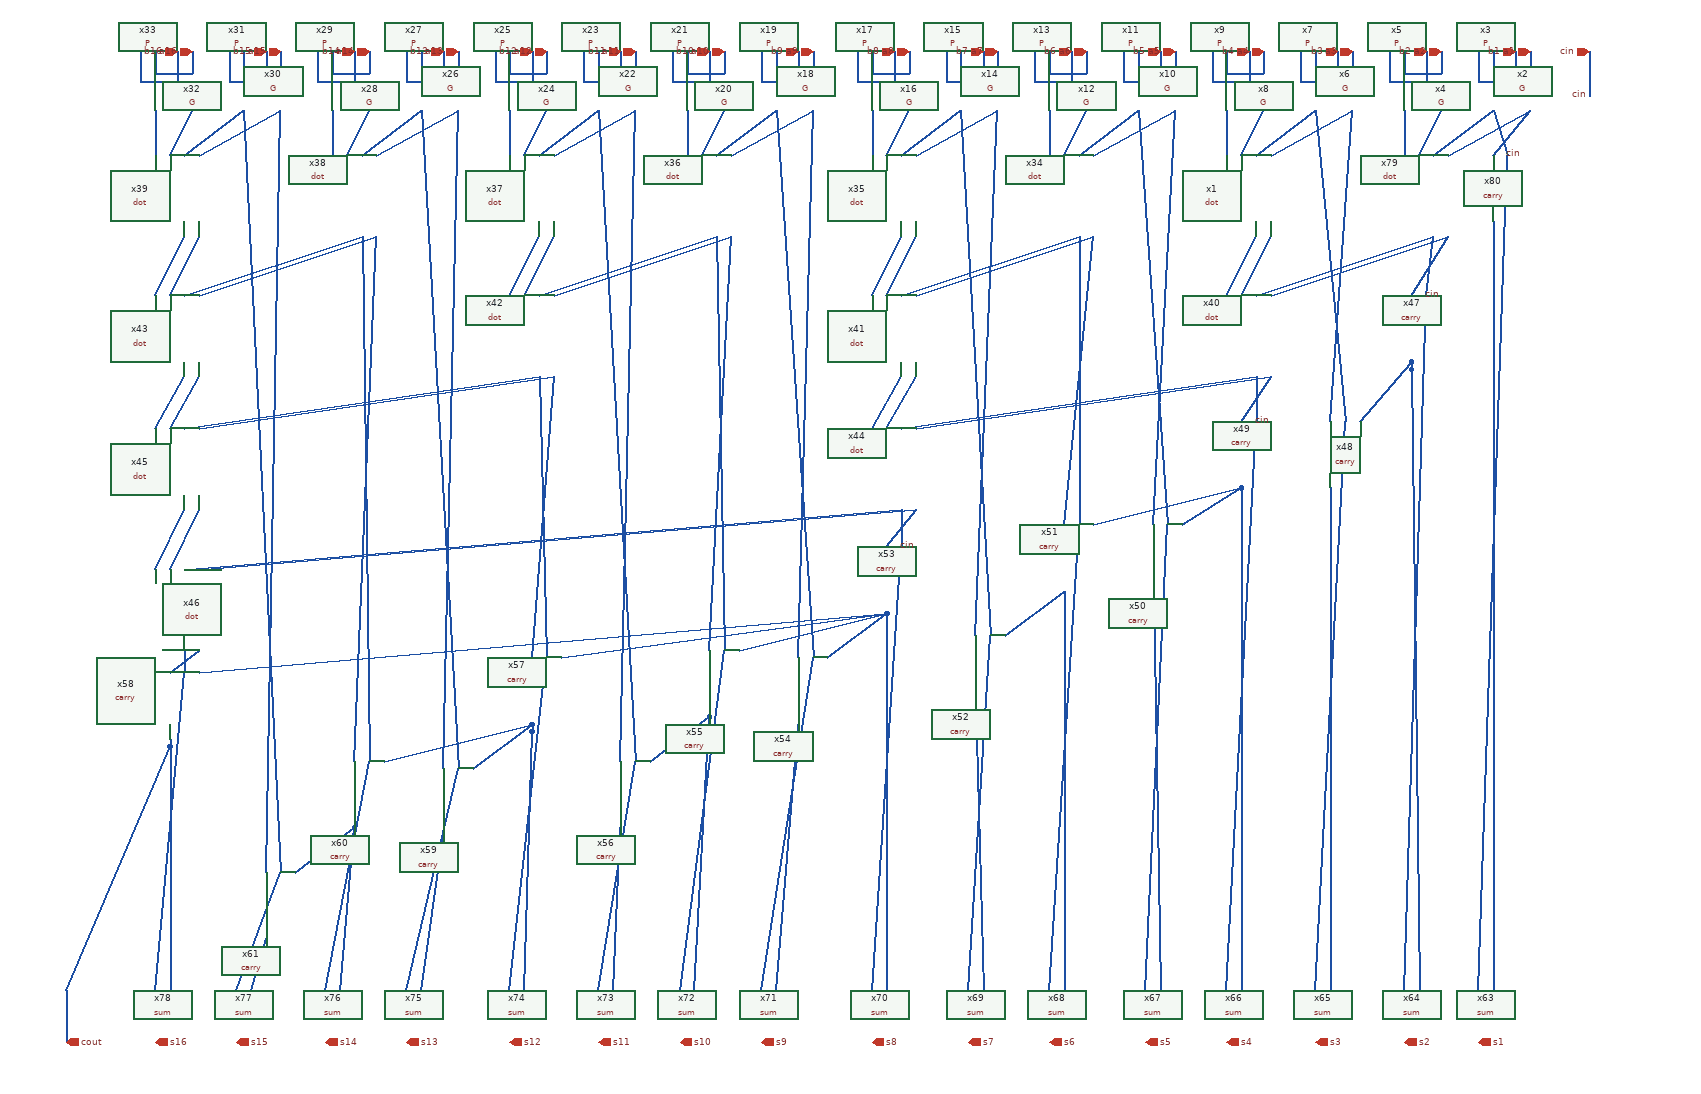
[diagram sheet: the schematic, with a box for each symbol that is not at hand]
v {xschem version=3.4.6 file_version=1.2}
G {}
K {}
V {}
S {}
E {}
N 1020 -110 1020 -50 {lab=cin}
N 940 -110 940 -80 {lab=a1}
N 890 -80 940 -80 {lab=a1}
N 890 -110 890 -80 {lab=a1}
N 920 -110 920 -70 {lab=b1}
N 870 -70 920 -70 {lab=b1}
N 870 -110 870 -70 {lab=b1}
N 820 -110 820 -80 {lab=a2}
N 770 -80 820 -80 {lab=a2}
N 770 -110 770 -80 {lab=a2}
N 800 -110 800 -70 {lab=b2}
N 750 -70 800 -70 {lab=b2}
N 750 -110 750 -70 {lab=b2}
N 700 -110 700 -80 {lab=a3}
N 650 -80 700 -80 {lab=a3}
N 650 -110 650 -80 {lab=a3}
N 680 -110 680 -70 {lab=b3}
N 630 -70 680 -70 {lab=b3}
N 630 -110 630 -70 {lab=b3}
N 580 -110 580 -80 {lab=a4}
N 530 -80 580 -80 {lab=a4}
N 530 -110 530 -80 {lab=a4}
N 560 -110 560 -70 {lab=b4}
N 510 -70 560 -70 {lab=b4}
N 510 -110 510 -70 {lab=b4}
N 460 -110 460 -80 {lab=a5}
N 410 -80 460 -80 {lab=a5}
N 410 -110 410 -80 {lab=a5}
N 440 -110 440 -70 {lab=b5}
N 390 -70 440 -70 {lab=b5}
N 390 -110 390 -70 {lab=b5}
N 340 -110 340 -80 {lab=a6}
N 290 -80 340 -80 {lab=a6}
N 290 -110 290 -80 {lab=a6}
N 320 -110 320 -70 {lab=b6}
N 270 -70 320 -70 {lab=b6}
N 270 -110 270 -70 {lab=b6}
N 220 -110 220 -80 {lab=a7}
N 170 -80 220 -80 {lab=a7}
N 170 -110 170 -80 {lab=a7}
N 200 -110 200 -70 {lab=b7}
N 150 -70 200 -70 {lab=b7}
N 150 -110 150 -70 {lab=b7}
N 100 -110 100 -80 {lab=a8}
N 50 -80 100 -80 {lab=a8}
N 50 -110 50 -80 {lab=a8}
N 80 -110 80 -70 {lab=b8}
N 30 -70 80 -70 {lab=b8}
N 30 -110 30 -70 {lab=b8}
N -30 -110 -30 -80 {lab=a9}
N -80 -80 -30 -80 {lab=a9}
N -80 -110 -80 -80 {lab=a9}
N -50 -110 -50 -70 {lab=b9}
N -100 -70 -50 -70 {lab=b9}
N -100 -110 -100 -70 {lab=b9}
N -150 -110 -150 -80 {lab=a10}
N -200 -80 -150 -80 {lab=a10}
N -200 -110 -200 -80 {lab=a10}
N -170 -110 -170 -70 {lab=b10}
N -220 -70 -170 -70 {lab=b10}
N -220 -110 -220 -70 {lab=b10}
N -270 -110 -270 -80 {lab=a11}
N -320 -80 -270 -80 {lab=a11}
N -320 -110 -320 -80 {lab=a11}
N -290 -110 -290 -70 {lab=b11}
N -340 -70 -290 -70 {lab=b11}
N -340 -110 -340 -70 {lab=b11}
N -390 -110 -390 -80 {lab=a12}
N -440 -80 -390 -80 {lab=a12}
N -440 -110 -440 -80 {lab=a12}
N -410 -110 -410 -70 {lab=b12}
N -460 -70 -410 -70 {lab=b12}
N -460 -110 -460 -70 {lab=b12}
N -510 -110 -510 -80 {lab=a13}
N -560 -80 -510 -80 {lab=a13}
N -560 -110 -560 -80 {lab=a13}
N -530 -110 -530 -70 {lab=b13}
N -580 -70 -530 -70 {lab=b13}
N -580 -110 -580 -70 {lab=b13}
N -630 -110 -630 -80 {lab=a14}
N -680 -80 -630 -80 {lab=a14}
N -680 -110 -680 -80 {lab=a14}
N -650 -110 -650 -70 {lab=b14}
N -700 -70 -650 -70 {lab=b14}
N -700 -110 -700 -70 {lab=b14}
N -750 -110 -750 -80 {lab=a15}
N -800 -80 -750 -80 {lab=a15}
N -800 -110 -800 -80 {lab=a15}
N -770 -110 -770 -70 {lab=b15}
N -820 -70 -770 -70 {lab=b15}
N -820 -110 -820 -70 {lab=b15}
N -870 -110 -870 -80 {lab=a16}
N -920 -80 -870 -80 {lab=a16}
N -920 -110 -920 -80 {lab=a16}
N -890 -110 -890 -70 {lab=b16}
N -940 -70 -890 -70 {lab=b16}
N -940 -110 -940 -70 {lab=b16}
N -1040 1160 -1040 1230 {lab=cout}
N 770 -30 770 30 {lab=#net1}
N 790 30 820 -30 {lab=#net2}
N 810 30 890 -30 {lab=#net3}
N 830 30 940 -30 {lab=#net4}
N 530 -30 530 30 {lab=#net5}
N 550 30 580 -30 {lab=#net6}
N 570 30 650 -30 {lab=#net7}
N 590 30 700 -30 {lab=#net8}
N 290 -30 290 30 {lab=#net9}
N 310 30 340 -30 {lab=#net10}
N 330 30 410 -30 {lab=#net11}
N 350 30 460 -30 {lab=#net12}
N 50 -30 50 30 {lab=#net13}
N 70 30 100 -30 {lab=#net14}
N 90 30 170 -30 {lab=#net15}
N 110 30 220 -30 {lab=#net16}
N -200 -30 -200 30 {lab=#net17}
N -180 30 -150 -30 {lab=#net18}
N -160 30 -80 -30 {lab=#net19}
N -140 30 -30 -30 {lab=#net20}
N -440 -30 -440 30 {lab=#net21}
N -420 30 -390 -30 {lab=#net22}
N -400 30 -320 -30 {lab=#net23}
N -380 30 -270 -30 {lab=#net24}
N -680 -30 -680 30 {lab=#net25}
N -660 30 -630 -30 {lab=#net26}
N -640 30 -560 -30 {lab=#net27}
N -620 30 -510 -30 {lab=#net28}
N -920 -30 -920 30 {lab=#net29}
N -900 30 -870 -30 {lab=#net30}
N -880 30 -800 -30 {lab=#net31}
N -860 30 -750 -30 {lab=#net32}
N 530 220 570 140 {lab=#net33}
N 550 220 590 140 {lab=#net34}
N 570 220 810 140 {lab=#net35}
N 590 220 830 140 {lab=#net36}
N 50 220 90 140 {lab=#net37}
N 70 220 110 140 {lab=#net38}
N 90 220 330 140 {lab=#net39}
N 110 220 350 140 {lab=#net40}
N -440 220 -400 140 {lab=#net41}
N -420 220 -380 140 {lab=#net42}
N -400 220 -160 140 {lab=#net43}
N -380 220 -140 140 {lab=#net44}
N -920 220 -880 140 {lab=#net45}
N -900 220 -860 140 {lab=#net46}
N -880 220 -640 140 {lab=#net47}
N -860 220 -620 140 {lab=#net48}
N 50 400 90 330 {lab=#net49}
N 70 400 110 330 {lab=#net50}
N 90 400 570 330 {lab=#net51}
N 110 400 590 330 {lab=#net52}
N -920 400 -880 330 {lab=#net53}
N -900 400 -860 330 {lab=#net54}
N -880 400 -400 330 {lab=#net55}
N -860 400 -380 330 {lab=#net56}
N -920 590 -880 510 {lab=#net57}
N -900 590 -860 510 {lab=#net58}
N -880 590 90 510 {lab=#net59}
N -860 590 110 510 {lab=#net60}
N 890 30 940 -30 {lab=#net4}
N 890 -30 910 30 {lab=#net3}
N 780 220 830 140 {lab=#net36}
N 800 220 810 140 {lab=#net35}
N 550 390 590 330 {lab=#net52}
N 570 330 570 390 {lab=#net51}
N 650 -30 690 390 {lab=#net7}
N 670 390 700 -30 {lab=#net8}
N 710 390 780 310 {lab=#net61}
N 470 530 550 480 {lab=#net62}
N 230 680 310 620 {lab=#net63}
N 70 560 110 510 {lab=#net60}
N 90 510 90 560 {lab=#net59}
N 350 530 550 480 {lab=#net62}
N 330 140 330 530 {lab=#net39}
N 310 530 350 140 {lab=#net40}
N -10 710 70 650 {lab=#net64}
N -130 700 70 650 {lab=#net64}
N -250 850 -170 790 {lab=#net65}
N -370 710 70 650 {lab=#net64}
N -860 730 70 650 {lab=#net64}
N -490 860 -410 800 {lab=#net66}
N -610 850 -410 800 {lab=#net66}
N -730 1000 -650 940 {lab=#net67}
N -900 830 -900 1160 {lab=cout}
N -920 1160 -880 730 {lab=#net68}
N -880 700 -880 730 {lab=#net68}
N -900 730 -860 700 {lab=#net69}
N -790 1160 -770 1090 {lab=#net70}
N -810 1160 -750 1000 {lab=#net31}
N -800 -30 -750 1000 {lab=#net31}
N -770 1000 -750 -30 {lab=#net32}
N -690 1160 -630 850 {lab=#net47}
N -670 1160 -650 940 {lab=#net67}
N -640 140 -630 850 {lab=#net47}
N -650 850 -620 140 {lab=#net48}
N -560 1160 -530 950 {lab=#net71}
N -580 1160 -510 860 {lab=#net27}
N -560 -30 -510 860 {lab=#net27}
N -530 860 -510 -30 {lab=#net28}
N -420 1160 -410 810 {lab=#net66}
N -440 1160 -390 710 {lab=#net55}
N -400 330 -390 710 {lab=#net55}
N -410 710 -380 330 {lab=#net56}
N -300 1160 -290 940 {lab=#net72}
N -320 1160 -270 850 {lab=#net23}
N -320 -30 -270 850 {lab=#net23}
N -290 850 -270 -30 {lab=#net24}
N -190 1160 -170 790 {lab=#net65}
N -210 1160 -150 700 {lab=#net43}
N -160 140 -150 700 {lab=#net43}
N -170 700 -140 140 {lab=#net44}
N -80 -30 -30 710 {lab=#net19}
N -100 1160 -30 710 {lab=#net19}
N -80 1160 -50 800 {lab=#net73}
N -50 710 -30 -30 {lab=#net20}
N 50 1160 90 560 {lab=#net59}
N 70 650 70 1160 {lab=#net64}
N 190 770 200 1160 {lab=#net74}
N 180 1160 210 680 {lab=#net15}
N 170 -30 210 680 {lab=#net15}
N 190 680 220 -30 {lab=#net16}
N 310 620 310 1160 {lab=#net63}
N 290 1160 330 530 {lab=#net39}
N 430 620 440 1160 {lab=#net75}
N 420 1160 450 530 {lab=#net11}
N 430 530 460 -30 {lab=#net12}
N 410 -30 450 530 {lab=#net11}
N 550 480 550 1160 {lab=#net62}
N 670 480 670 1160 {lab=#net76}
N 530 1160 570 390 {lab=#net51}
N 650 1160 690 390 {lab=#net7}
N 780 320 790 1160 {lab=#net61}
N 770 1160 800 220 {lab=#net35}
N 890 120 890 1160 {lab=#net77}
N 870 1160 910 30 {lab=#net3}
N -1040 1160 -900 830 {lab=cout}
N -900 820 -900 830 {lab=cout}
N -770 1090 -770 1100 {lab=#net70}
N -530 950 -530 960 {lab=#net71}
N -410 800 -410 810 {lab=#net66}
N 190 770 190 780 {lab=#net74}
N 780 310 780 320 {lab=#net61}
N -290 940 -290 950 {lab=#net72}
N -170 790 -170 800 {lab=#net65}
N -650 940 -650 950 {lab=#net67}
N -50 800 -50 810 {lab=#net73}
N 430 620 430 630 {lab=#net75}
N 780 310 780 320 {lab=#net61}
N -410 800 -410 810 {lab=#net66}
C {G.sym} 930 -70 1 0 {name=x2}
C {P.sym} 880 -70 1 0 {name=x3}
C {G.sym} 810 -70 1 0 {name=x4}
C {P.sym} 760 -70 1 0 {name=x5}
C {G.sym} 690 -70 1 0 {name=x6}
C {P.sym} 640 -70 1 0 {name=x7}
C {G.sym} 570 -70 1 0 {name=x8}
C {P.sym} 520 -70 1 0 {name=x9}
C {G.sym} 450 -70 1 0 {name=x10}
C {P.sym} 400 -70 1 0 {name=x11}
C {G.sym} 330 -70 1 0 {name=x12}
C {P.sym} 280 -70 1 0 {name=x13}
C {G.sym} 210 -70 1 0 {name=x14}
C {P.sym} 160 -70 1 0 {name=x15}
C {G.sym} 90 -70 1 0 {name=x16}
C {P.sym} 40 -70 1 0 {name=x17}
C {G.sym} -40 -70 1 0 {name=x18}
C {P.sym} -90 -70 1 0 {name=x19}
C {G.sym} -160 -70 1 0 {name=x20}
C {P.sym} -210 -70 1 0 {name=x21}
C {G.sym} -280 -70 1 0 {name=x22}
C {P.sym} -330 -70 1 0 {name=x23}
C {G.sym} -400 -70 1 0 {name=x24}
C {P.sym} -450 -70 1 0 {name=x25}
C {G.sym} -520 -70 1 0 {name=x26}
C {P.sym} -570 -70 1 0 {name=x27}
C {G.sym} -640 -70 1 0 {name=x28}
C {P.sym} -690 -70 1 0 {name=x29}
C {G.sym} -760 -70 1 0 {name=x30}
C {P.sym} -810 -70 1 0 {name=x31}
C {G.sym} -880 -70 1 0 {name=x32}
C {P.sym} -930 -70 1 0 {name=x33}
C {sum.sym} 880 1190 3 1 {name=x63}
C {sum.sym} 780 1190 3 1 {name=x64}
C {sum.sym} 660 1190 3 1 {name=x65}
C {sum.sym} 540 1190 3 1 {name=x66}
C {sum.sym} 430 1190 3 1 {name=x67}
C {sum.sym} 300 1190 3 1 {name=x68}
C {sum.sym} 190 1190 3 1 {name=x69}
C {sum.sym} 60 1190 3 1 {name=x70}
C {sum.sym} -90 1190 3 1 {name=x71}
C {sum.sym} -200 1190 3 1 {name=x72}
C {sum.sym} -310 1190 3 1 {name=x73}
C {sum.sym} -430 1190 3 1 {name=x74}
C {sum.sym} -570 1190 3 1 {name=x75}
C {sum.sym} -680 1190 3 1 {name=x76}
C {sum.sym} -800 1190 3 1 {name=x77}
C {sum.sym} -910 1190 3 1 {name=x78}
C {ipin.sym} -890 -110 1 0 {name=p3 lab=b16}
C {ipin.sym} -870 -110 1 0 {name=p4 lab=a16}
C {ipin.sym} -770 -110 1 0 {name=p7 lab=b15}
C {ipin.sym} -750 -110 1 0 {name=p8 lab=a15}
C {ipin.sym} -650 -110 1 0 {name=p11 lab=b14}
C {ipin.sym} -630 -110 1 0 {name=p12 lab=a14}
C {ipin.sym} -530 -110 1 0 {name=p15 lab=b13}
C {ipin.sym} -510 -110 1 0 {name=p16 lab=a13}
C {ipin.sym} -410 -110 1 0 {name=p19 lab=b12}
C {ipin.sym} -390 -110 1 0 {name=p20 lab=a12}
C {ipin.sym} -290 -110 1 0 {name=p23 lab=b11}
C {ipin.sym} -270 -110 1 0 {name=p24 lab=a11}
C {ipin.sym} -170 -110 1 0 {name=p27 lab=b10}
C {ipin.sym} -150 -110 1 0 {name=p28 lab=a10}
C {ipin.sym} -50 -110 1 0 {name=p31 lab=b9}
C {ipin.sym} -30 -110 1 0 {name=p32 lab=a9}
C {ipin.sym} 80 -110 1 0 {name=p35 lab=b8}
C {ipin.sym} 100 -110 1 0 {name=p36 lab=a8}
C {ipin.sym} 200 -110 1 0 {name=p39 lab=b7}
C {ipin.sym} 220 -110 1 0 {name=p40 lab=a7}
C {ipin.sym} 320 -110 1 0 {name=p43 lab=b6}
C {ipin.sym} 340 -110 1 0 {name=p44 lab=a6}
C {ipin.sym} 440 -110 1 0 {name=p47 lab=b5}
C {ipin.sym} 460 -110 1 0 {name=p48 lab=a5}
C {ipin.sym} 560 -110 1 0 {name=p51 lab=b4}
C {ipin.sym} 580 -110 1 0 {name=p52 lab=a4}
C {ipin.sym} 680 -110 1 0 {name=p55 lab=b3}
C {ipin.sym} 700 -110 1 0 {name=p56 lab=a3}
C {ipin.sym} 800 -110 1 0 {name=p59 lab=b2}
C {ipin.sym} 820 -110 1 0 {name=p60 lab=a2}
C {ipin.sym} 920 -110 1 0 {name=p63 lab=b1}
C {ipin.sym} 940 -110 1 0 {name=p64 lab=a1}
C {ipin.sym} 1020 -110 1 0 {name=p65 lab=cin}
C {opin.sym} 870 1230 1 0 {name=p1 lab=s1}
C {opin.sym} 770 1230 1 0 {name=p2 lab=s2}
C {opin.sym} 650 1230 1 0 {name=p5 lab=s3}
C {opin.sym} 530 1230 1 0 {name=p6 lab=s4}
C {opin.sym} 420 1230 1 0 {name=p9 lab=s5}
C {opin.sym} 290 1230 1 0 {name=p10 lab=s6}
C {opin.sym} 180 1230 1 0 {name=p13 lab=s7}
C {opin.sym} 50 1230 1 0 {name=p14 lab=s8}
C {opin.sym} -100 1230 1 0 {name=p17 lab=s9}
C {opin.sym} -210 1230 1 0 {name=p18 lab=s10}
C {opin.sym} -320 1230 1 0 {name=p21 lab=s11}
C {opin.sym} -440 1230 1 0 {name=p22 lab=s12}
C {opin.sym} -580 1230 1 0 {name=p25 lab=s13}
C {opin.sym} -690 1230 1 0 {name=p26 lab=s14}
C {opin.sym} -810 1230 1 0 {name=p29 lab=s15}
C {opin.sym} -920 1230 1 0 {name=p30 lab=s16}
C {opin.sym} -1040 1230 1 0 {name=p33 lab=cout}
C {dot.sym} 800 90 1 0 {name=x79}
C {carry.sym} 910 80 3 1 {name=x80}
C {dot.sym} 560 90 1 0 {name=x1}
C {dot.sym} 320 90 1 0 {name=x34}
C {dot.sym} 80 90 1 0 {name=x35}
C {dot.sym} -170 90 1 0 {name=x36}
C {dot.sym} -410 90 1 0 {name=x37}
C {dot.sym} -650 90 1 0 {name=x38}
C {dot.sym} -890 90 1 0 {name=x39}
C {dot.sym} 560 280 1 0 {name=x40}
C {dot.sym} 80 280 1 0 {name=x41}
C {dot.sym} -410 280 1 0 {name=x42}
C {dot.sym} -890 280 1 0 {name=x43}
C {dot.sym} 80 460 1 0 {name=x44}
C {dot.sym} -890 460 1 0 {name=x45}
C {dot.sym} -890 650 1 0 {name=x46}
C {carry.sym} 800 270 3 1 {name=x47}
C {lab_pin.sym} 820 220 1 0 {name=p34 sig_type=std_logic lab=cin}
C {lab_pin.sym} 930 30 1 0 {name=p37 sig_type=std_logic lab=cin}
C {lab_pin.sym} 1020 -50 1 1 {name=p38 sig_type=std_logic lab=cin}
C {carry.sym} 690 440 3 1 {name=x48}
C {carry.sym} 570 440 3 1 {name=x49}
C {lab_pin.sym} 590 390 1 0 {name=p41 sig_type=std_logic lab=cin}
C {carry.sym} 450 580 3 1 {name=x50}
C {carry.sym} 330 580 3 1 {name=x51}
C {carry.sym} 210 730 3 1 {name=x52}
C {carry.sym} 90 610 3 1 {name=x53}
C {lab_pin.sym} 110 560 1 0 {name=p42 sig_type=std_logic lab=cin}
C {carry.sym} -30 760 3 1 {name=x54}
C {carry.sym} -150 750 3 1 {name=x55}
C {carry.sym} -270 900 3 1 {name=x56}
C {carry.sym} -390 760 3 1 {name=x57}
C {carry.sym} -880 780 3 1 {name=x58}
C {carry.sym} -510 910 3 1 {name=x59}
C {carry.sym} -630 900 3 1 {name=x60}
C {carry.sym} -750 1050 3 1 {name=x61}
